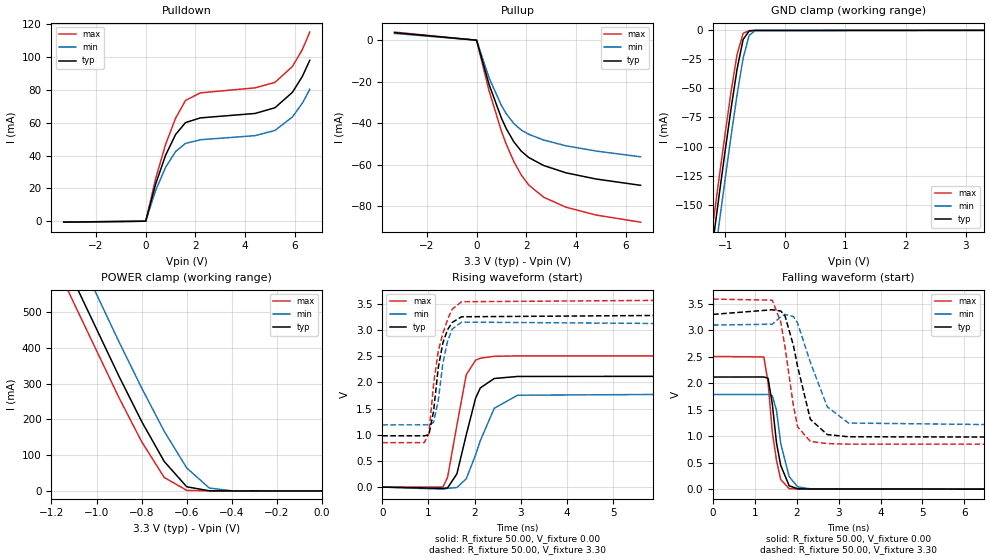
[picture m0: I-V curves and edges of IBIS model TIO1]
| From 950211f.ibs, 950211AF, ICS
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|   Model TIO1
[Model]   TIO1
Model_type   I/O
Enable   Active-High
Polarity   Non-Inverting
Vinl = 800.00mV
Vinh =   2.00V
C_comp   5.50pF   5.00pF   6.00pF
[Temperature Range]   27.00   70.00   0.00
[Voltage Range]   3.30V   3.00V   3.70V
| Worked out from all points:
|   slope of the pulldown table from 0 to 0.495 V, typ, clamps not added: 18.1 ohm
|   slope of the pullup table from 0 to 0.495 V, typ, clamps not added: 23.5 ohm
|   GND clamp passes 1 mA (typ) near -0.61 V on its own axis
|   POWER clamp passes 1 mA (typ) near -0.51 V on its own axis
|   rising waveform, R_fixture 50.00, V_fixture 0.00: 20-80 % time 352ps typ, 458ps min, 294ps max; typ from 0 V to 2.12 V
|   rising waveform, R_fixture 50.00, V_fixture 3.30: 20-80 % time 235ps typ, 204ps min, 302ps max; typ from 0.979 V to 3.3 V
|   falling waveform, R_fixture 50.00, V_fixture 0.00: 20-80 % time 228ps typ, 238ps min, 212ps max; typ from 2.12 V to 0 V
|   falling waveform, R_fixture 50.00, V_fixture 3.30: 20-80 % time 392ps typ, 513ps min, 323ps max; typ from 3.3 V to 0.979 V
[Pulldown]
| voltage   I(typ)   I(min)   I(max)
-3.3V     -554.5uA   -489.7uA   -601.7uA
0V        0A         49pA       0A
400mV     22.72mA    18.83mA    26.05mA
800mV     40.24mA    32.88mA    46.88mA
1.2V      52.83mA    42.47mA    62.74mA
1.6V      60.12mA    47.44mA    73.63mA
2.2V      62.99mA    49.67mA    78.26mA
4.4V      65.69mA    52.17mA    81.3mA
5.2V      69.19mA    55.34mA    84.65mA
5.9V      78.56mA    63.53mA    94.29mA
6.3V      88.25mA    71.91mA    104.6mA
6.6V      98.1mA     80.39mA    115.3mA
[Pullup]
| voltage   I(typ)   I(min)   I(max)
-3.3V     3.628mA    3.257mA    3.907mA
0V        -83.05fA   -1.329pA   -280.7fA
500mV     -21.21mA   -18.05mA   -24.27mA
1V        -37.56mA   -31.45mA   -43.79mA
1.2V      -42.71mA   -35.5mA    -50.26mA
1.5V      -48.95mA   -40.16mA   -58.48mA
1.8V      -53.45mA   -43.28mA   -64.95mA
2.1V      -56.5mA    -45.32mA   -69.74mA
2.7V      -60.35mA   -48.08mA   -75.62mA
3.6V      -63.88mA   -50.87mA   -80.45mA
4.8V      -66.84mA   -53.37mA   -84.18mA
6.6V      -69.89mA   -56.17mA   -87.65mA
[GND_clamp]
| voltage   I(typ)   I(min)   I(max)
-3.3V     -1.039A    -1.062A    -1.025A
-1.2V     -181.5mA   -205.8mA   -166.3mA
-1.1V     -142.3mA   -166.7mA   -127.2mA
-1V       -104mA     -128.2mA   -89.04mA
-900mV    -67.08mA   -90.71mA   -52.58mA
-800mV    -33.12mA   -55.16mA   -20.49mA
-700mV    -7.808mA   -23.9mA    -2.542mA
-600mV    -568uA     -4.238mA   -251.7uA
-500mV    -66.67uA   -270uA     -57.89uA
3.3V      54.6pA     18.21uA    -11.37uA
[POWER_clamp]
| voltage   I(typ)   I(min)   I(max)
-3.3V     3.69A      3.783A     3.632A
-1.3V     860.3mA    958.1mA    799.3mA
-1.2V     722.6mA    820.5mA    661.5mA
-1.1V     586.2mA    684.1mA    525.2mA
-900mV    320.4mA    416.9mA    260.5mA
-800mV    194.6mA    288.3mA    138mA
-700mV    82.59mA    167.2mA    37.77mA
-600mV    11.58mA    64.14mA    1.586mA
-500mV    342.8uA    8.115mA    39.37uA
-400mV    17.9uA     340.7uA    12.99uA
0V        54.6pA     109.7pA    59.36pA
[Ramp]
| variable   typ   min   max
dV/dt_r   1.297E+0/3.548E-10   1.096E+0/4.624E-10   1.533E+0/2.876E-10
dV/dt_f   1.465E+0/4.031E-10   1.268E+0/5.445E-10   1.691E+0/3.235E-10
[Rising Waveform]
R_fixture = 50.00
V_fixture = 0.00
| time   V(typ)   V(min)   V(max)
0s        362.6uV    309.7uV    448.3uV
1.313ns   -24.1mV    -39.06mV   1.321mV
1.414ns   -14.67mV   -23.31mV   187.5mV
1.616ns   253.6mV    -7.559mV   1.182V
1.818ns   997.5mV    159.8mV    2.143V
2.02ns    1.696V     612.3mV    2.422V
2.121ns   1.892V     882.1mV    2.46V
2.424ns   2.073V     1.505V     2.497V
2.929ns   2.112V     1.754V     2.505V
10ns      2.117V     1.787V     2.506V
[Rising Waveform]
R_fixture = 50.00
V_fixture = 3.30
| time   V(typ)   V(min)   V(max)
0s        978.8mV    1.188V     848.6mV
909.1ps   978.6mV    1.189V     848.9mV
1.01ns    999mV      1.187V     1.017V
1.111ns   1.445V     1.235V     1.961V
1.212ns   2.276V     1.651V     2.594V
1.313ns   2.756V     2.368V     2.937V
1.414ns   3.004V     2.789V     3.201V
1.515ns   3.144V     3.016V     3.397V
1.717ns   3.251V     3.149V     3.538V
10ns      3.3V       3.098V     3.589V
[Falling Waveform]
R_fixture = 50.00
V_fixture = 0.00
| time   V(typ)   V(min)   V(max)
0s        2.117V     1.787V     2.506V
1.212ns   2.118V     1.787V     2.496V
1.313ns   2.095V     1.789V     2.022V
1.414ns   1.615V     1.767V     1.081V
1.515ns   872.9mV    1.486V     542.7mV
1.616ns   448mV      861.7mV    181mV
1.818ns   63.05mV    235.3mV    10.17mV
2.02ns    8.216mV    44.61mV    4.482mV
2.323ns   3.308mV    6.292mV    1.964mV
10ns      371.6uV    301.2uV    436.2uV
[Falling Waveform]
R_fixture = 50.00
V_fixture = 3.30
| time   V(typ)   V(min)   V(max)
0s        3.3V       3.098V     3.589V
1.414ns   3.387V     3.114V     3.568V
1.616ns   3.363V     3.253V     3.155V
1.717ns   3.274V     3.3V       2.687V
1.919ns   2.711V     3.258V     1.572V
2.02ns    2.311V     3.134V     1.176V
2.323ns   1.319V     2.396V     902mV
2.727ns   1.031V     1.555V     860.4mV
3.232ns   989.5mV    1.249V     850.5mV
10ns      978.9mV    1.189V     848.6mV
